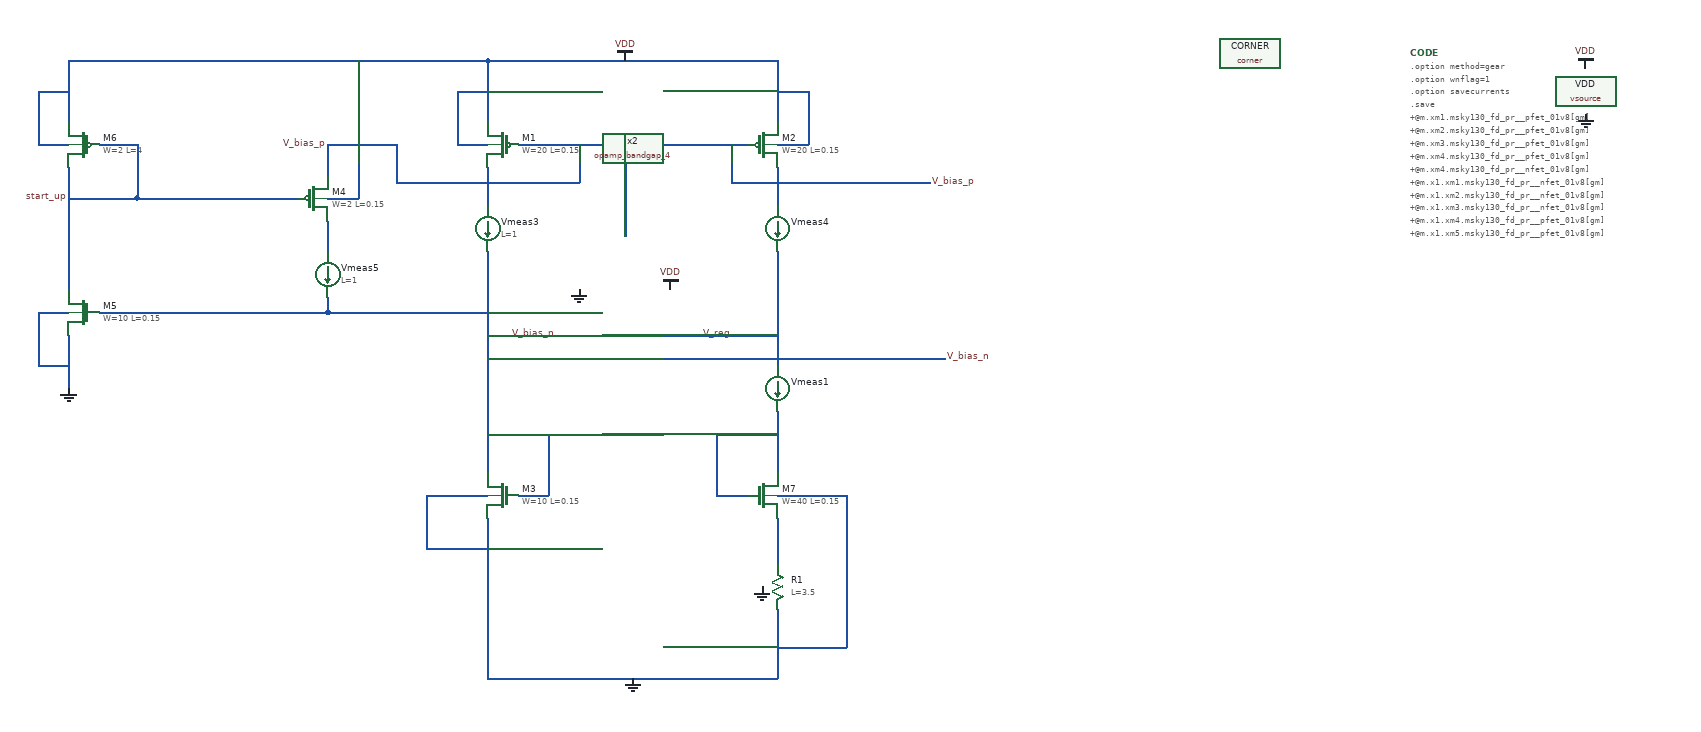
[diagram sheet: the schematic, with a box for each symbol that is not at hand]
v {xschem version=3.4.6 file_version=1.2}
G {}
K {}
V {}
S {}
E {}
B 2 1490 -1230 2100 -680 {flags=graph

y2=1.5701622
ypos1=0
ypos2=2
divy=5
subdivy=4
unity=1
x1=0
x2=2
divx=5
subdivx=4
xlabmag=1.0
ylabmag=1.0


dataset=-1
unitx=1
logx=0
logy=0











linewidth_mult=4
























y1=-0.029837768



color=6
node=v_bias_p}
B 2 760 -1660 990 -1500 {flags=graph

y2=0.00028
ypos1=0
ypos2=2
divy=5
subdivy=4
unity=1
x1=0
x2=2
divx=5
subdivx=4
xlabmag=1.0
ylabmag=1.0


dataset=-1
unitx=1
logx=0
logy=0











linewidth_mult=1
























y1=-3.2e-05



color=12
node=i(vmeas5)}
B 2 460 -1660 690 -1500 {flags=graph

y2=0.85
ypos1=0
ypos2=2
divy=5
subdivy=4
unity=1
x1=0
x2=2
divx=5
subdivx=4
xlabmag=1.0
ylabmag=1.0


dataset=-1
unitx=1
logx=0
logy=0











linewidth_mult=1
























y1=2.5e-16


color="6 7"
node="v_top
vin-"}
B 2 0 -1660 230 -1480 {flags=graph

y2=1.8
ypos1=0
ypos2=2
divy=5
subdivy=4
unity=1
x1=0
x2=2
divx=5
subdivx=4
xlabmag=1.0
ylabmag=1.0


dataset=-1
unitx=1
logx=0
logy=0











linewidth_mult=1
























y1=-0.61



node="v_out
start_up
vdd
vin-
v_top"
color="7 6 12 18 11"}
B 2 -400 -1270 -170 -1060 {flags=graph

y2=0.00028
ypos1=0
ypos2=2
divy=5
subdivy=4
unity=1
x1=0
x2=2
divx=5
subdivx=4
xlabmag=1.0
ylabmag=1.0


dataset=-1
unitx=1
logx=0
logy=0











linewidth_mult=1
























y1=6.5e-17



color=6
node=i(@m.xm4.msky130_fd_pr__pfet_01v8[id])}
B 2 1490 -610 2100 -60 {flags=graph

y2=1.5e-05
ypos1=0
ypos2=2
divy=5
subdivy=4
unity=1
x1=0
x2=2
divx=5
subdivx=4
xlabmag=1.0
ylabmag=1.0


dataset=-1
unitx=1
logx=0
logy=0











linewidth_mult=4
























y1=-2.3e-29




color=6
node=i(vmeas1)}
N 520 -1340 660 -1340 {
lab=V_bias_p}
N 660 -1340 820 -1340 {
lab=V_bias_p}
N 480 -1450 480 -1370 {
lab=VDD}
N 480 -1450 860 -1450 {
lab=VDD}
N 860 -1450 860 -1370 {
lab=VDD}
N 860 -730 860 -640 {lab=GND}
N 860 -1340 900 -1340 {lab=VDD}
N 900 -1410 900 -1340 {lab=VDD}
N 860 -1410 900 -1410 {lab=VDD}
N 440 -1340 480 -1340 {lab=VDD}
N 440 -1410 440 -1340 {lab=VDD}
N 440 -1410 480 -1410 {lab=VDD}
N 800 -1340 800 -1290 {lab=V_bias_p}
N 800 -1290 1060 -1290 {lab=V_bias_p}
N 860 -1310 860 -1260 {lab=#net1}
N 480 -1310 480 -1260 {lab=#net2}
N 270 -1340 270 -1300 {lab=V_bias_p}
N -70 -1240 -70 -1150 {lab=start_up}
N -70 -1450 -70 -1370 {
lab=VDD}
N -110 -1340 -70 -1340 {lab=VDD}
N -110 -1410 -110 -1340 {lab=VDD}
N -110 -1410 -70 -1410 {lab=VDD}
N -70 -1310 -70 -1240 {lab=start_up}
N -70 -1450 480 -1450 {lab=VDD}
N 270 -1340 360 -1340 {lab=V_bias_p}
N 360 -1340 360 -1290 {lab=V_bias_p}
N 360 -1290 600 -1290 {lab=V_bias_p}
N 480 -1200 480 -910 {lab=V_bias_n}
N 860 -1200 860 -1050 {lab=V_reg}
N 600 -1340 600 -1290 {lab=V_bias_p}
N 270 -1120 480 -1120 {lab=V_bias_n}
N -110 -1050 -70 -1050 {lab=GND}
N -110 -1120 -110 -1050 {lab=GND}
N -110 -1120 -70 -1120 {lab=GND}
N -70 -1090 -70 -1020 {lab=GND}
N 270 -1270 310 -1270 {lab=VDD}
N 270 -1140 270 -1120 {lab=V_bias_n}
N 270 -1240 270 -1200 {lab=#net3}
N 480 -850 480 -640 {lab=GND}
N 480 -640 860 -640 {lab=GND}
N 860 -850 860 -790 {lab=#net4}
N 860 -990 860 -910 {lab=#net5}
N 780 -880 820 -880 {lab=#net5}
N 780 -960 780 -880 {lab=#net5}
N 780 -960 860 -960 {lab=#net5}
N 520 -880 560 -880 {lab=V_bias_n}
N 560 -960 560 -880 {lab=V_bias_n}
N 480 -960 560 -960 {lab=V_bias_n}
N -70 -1270 20 -1270 {lab=start_up}
N 20 -1340 20 -1270 {lab=start_up}
N 310 -1450 310 -1270 {lab=VDD}
N -30 -1120 270 -1120 {lab=V_bias_n}
N 20 -1270 230 -1270 {lab=start_up}
N -30 -1340 20 -1340 {lab=start_up}
N 400 -880 480 -880 {lab=GND}
N 400 -880 400 -810 {lab=GND}
N 400 -810 480 -810 {lab=GND}
N 860 -680 950 -680 {lab=GND}
N 950 -880 950 -680 {lab=GND}
N 860 -880 950 -880 {lab=GND}
N 680 -1090 860 -1090 {lab=V_reg}
N 480 -1090 640 -1090 {lab=V_bias_n}
N 660 -1340 660 -1220 {lab=V_bias_p}
N 480 -1060 1080 -1060 {lab=V_bias_n}
C {devices/vsource.sym} 1920 -1410 0 0 {name=VDD value=1.8 savecurrent=false
* "pwl(0 0 1us 0 2us 1.8)"}
C {devices/gnd.sym} 1920 -1380 0 0 {name=l3 lab=GND}
C {devices/vdd.sym} 1920 -1440 0 0 {name=l4 lab=VDD}
C {sky130_fd_pr/corner.sym} 1480 -1460 0 0 {name=CORNER only_toplevel=false corner=tt}
C {devices/code.sym} 1690 -1460 0 0 {name=CODE only_toplevel=false value="

.option method=gear
.option wnflag=1
.option savecurrents

.save
+@m.xm1.msky130_fd_pr__pfet_01v8[gm]
+@m.xm2.msky130_fd_pr__pfet_01v8[gm]
+@m.xm3.msky130_fd_pr__pfet_01v8[gm]
+@m.xm4.msky130_fd_pr__pfet_01v8[gm]
+@m.xm4.msky130_fd_pr__nfet_01v8[gm]
+@m.x1.xm1.msky130_fd_pr__nfet_01v8[gm]
+@m.x1.xm2.msky130_fd_pr__nfet_01v8[gm]
+@m.x1.xm3.msky130_fd_pr__nfet_01v8[gm]
+@m.x1.xm4.msky130_fd_pr__pfet_01v8[gm]
+@m.x1.xm5.msky130_fd_pr__pfet_01v8[gm]
+@m.x1.xm6.msky130_fd_pr__nfet_01v8[gm]
+@m.x1.xm7.msky130_fd_pr__pfet_01v8[gm]
+@m.x2.xm1.msky130_fd_pr__nfet_01v8[gm]
+@m.x2.xm2.msky130_fd_pr__nfet_01v8[gm]
+@m.x2.xm3.msky130_fd_pr__nfet_01v8[gm]
+@m.x2.xm4.msky130_fd_pr__pfet_01v8[gm]
+@m.x2.xm5.msky130_fd_pr__pfet_01v8[gm]
+@m.x2.xm6.msky130_fd_pr__pfet_01v8[gm]
+@m.x2.xm7.msky130_fd_pr__pfet_01v8[gm]

* .ic v(vin-) = 0.8
.ic v(v_top) = 1.8

.control
  save all
  * dc temp -40 120 10 VDD 0 4.0 0.2
  dc VDD 0 2.0 0.01 temp -40 120 40
  * dc VDD 0 4.0 0.2
  * tran 1ns 10us
  remzerovec
  write tb_low_voltage_BGR_4.raw
  set appendwrite
.endc


"}
C {devices/vdd.sym} 720 -1150 1 0 {name=l5 lab=VDD}
C {devices/gnd.sym} 600 -1150 1 0 {name=l8 lab=GND
W=4}
C {devices/vdd.sym} 660 -1450 0 0 {name=l2 lab=VDD}
C {devices/gnd.sym} 840 -760 1 0 {name=l6 lab=GND}
C {sky130_fd_pr/pfet_01v8.sym} 500 -1340 0 1 {name=M1
W=20
L=0.15
nf=1
mult=1
ad="'int((nf+1)/2) * W/nf * 0.29'" 
pd="'2*int((nf+1)/2) * (W/nf + 0.29)'"
as="'int((nf+2)/2) * W/nf * 0.29'" 
ps="'2*int((nf+2)/2) * (W/nf + 0.29)'"
nrd="'0.29 / W'" nrs="'0.29 / W'"
sa=0 sb=0 sd=0
model=pfet_01v8
spiceprefix=X
}
C {sky130_fd_pr/pfet_01v8.sym} 840 -1340 0 0 {name=M2
W=20
L=0.15
nf=1
mult=1
ad="'int((nf+1)/2) * W/nf * 0.29'" 
pd="'2*int((nf+1)/2) * (W/nf + 0.29)'"
as="'int((nf+2)/2) * W/nf * 0.29'" 
ps="'2*int((nf+2)/2) * (W/nf + 0.29)'"
nrd="'0.29 / W'" nrs="'0.29 / W'"
sa=0 sb=0 sd=0
model=pfet_01v8
spiceprefix=X
}
C {lab_wire.sym} 1060 -1290 0 1 {name=p2 sig_type=std_logic lab=V_bias_p}
C {lab_wire.sym} 760 -1090 2 0 {name=p6 sig_type=std_logic lab=V_reg}
C {lab_wire.sym} 570 -1090 2 1 {name=p1 sig_type=std_logic lab=V_bias_n}
C {ammeter.sym} 860 -1020 0 0 {name=Vmeas1 savecurrent=true spice_ignore=0}
C {sky130_fd_pr/res_xhigh_po_0p35.sym} 860 -760 0 0 {name=R1
L=3.5
model=res_xhigh_po_0p35
spiceprefix=X
mult=1}
C {ammeter.sym} 480 -1230 0 0 {name=Vmeas3 savecurrent=true spice_ignore=0
L=1}
C {ammeter.sym} 860 -1230 0 0 {name=Vmeas4 savecurrent=true spice_ignore=0}
C {sky130_fd_pr/nfet_01v8.sym} -50 -1120 0 1 {name=M5
W=10
L=0.15
nf=1 
mult=1
ad="'int((nf+1)/2) * W/nf * 0.29'" 
pd="'2*int((nf+1)/2) * (W/nf + 0.29)'"
as="'int((nf+2)/2) * W/nf * 0.29'" 
ps="'2*int((nf+2)/2) * (W/nf + 0.29)'"
nrd="'0.29 / W'" nrs="'0.29 / W'"
sa=0 sb=0 sd=0
model=nfet_01v8
spiceprefix=X
}
C {sky130_fd_pr/pfet_01v8.sym} -50 -1340 0 1 {name=M6
W=2
L=4
nf=1
mult=1
ad="'int((nf+1)/2) * W/nf * 0.29'" 
pd="'2*int((nf+1)/2) * (W/nf + 0.29)'"
as="'int((nf+2)/2) * W/nf * 0.29'" 
ps="'2*int((nf+2)/2) * (W/nf + 0.29)'"
nrd="'0.29 / W'" nrs="'0.29 / W'"
sa=0 sb=0 sd=0
model=pfet_01v8
spiceprefix=X
}
C {devices/lab_pin.sym} -70 -1270 2 1 {name=p7 sig_type=std_logic lab=start_up}
C {ammeter.sym} 270 -1170 0 0 {name=Vmeas5 savecurrent=true spice_ignore=0
L=1}
C {sky130_fd_pr/pfet_01v8.sym} 250 -1270 0 0 {name=M4
W=2
L=0.15
nf=1
mult=1
ad="'int((nf+1)/2) * W/nf * 0.29'" 
pd="'2*int((nf+1)/2) * (W/nf + 0.29)'"
as="'int((nf+2)/2) * W/nf * 0.29'" 
ps="'2*int((nf+2)/2) * (W/nf + 0.29)'"
nrd="'0.29 / W'" nrs="'0.29 / W'"
sa=0 sb=0 sd=0
model=pfet_01v8
spiceprefix=X
}
C {opamp_bandgap_4.sym} 660 -1150 1 1 {name=x2}
C {sky130_fd_pr/nfet_01v8.sym} 500 -880 0 1 {name=M3
W=10
L=0.15
nf=1 
mult=1
ad="'int((nf+1)/2) * W/nf * 0.29'" 
pd="'2*int((nf+1)/2) * (W/nf + 0.29)'"
as="'int((nf+2)/2) * W/nf * 0.29'" 
ps="'2*int((nf+2)/2) * (W/nf + 0.29)'"
nrd="'0.29 / W'" nrs="'0.29 / W'"
sa=0 sb=0 sd=0
model=nfet_01v8
spiceprefix=X
}
C {sky130_fd_pr/nfet_01v8.sym} 840 -880 0 0 {name=M7
W=40
L=0.15
nf=1 
mult=1
ad="'int((nf+1)/2) * W/nf * 0.29'" 
pd="'2*int((nf+1)/2) * (W/nf + 0.29)'"
as="'int((nf+2)/2) * W/nf * 0.29'" 
ps="'2*int((nf+2)/2) * (W/nf + 0.29)'"
nrd="'0.29 / W'" nrs="'0.29 / W'"
sa=0 sb=0 sd=0
model=nfet_01v8
spiceprefix=X
}
C {devices/gnd.sym} 670 -640 0 0 {name=l1 lab=GND
W=4}
C {devices/gnd.sym} -70 -1020 0 0 {name=l7 lab=GND
W=4}
C {lab_wire.sym} 1080 -1060 0 1 {name=p4 sig_type=std_logic lab=V_bias_n}
C {lab_wire.sym} 270 -1340 0 0 {name=p3 sig_type=std_logic lab=V_bias_p}
